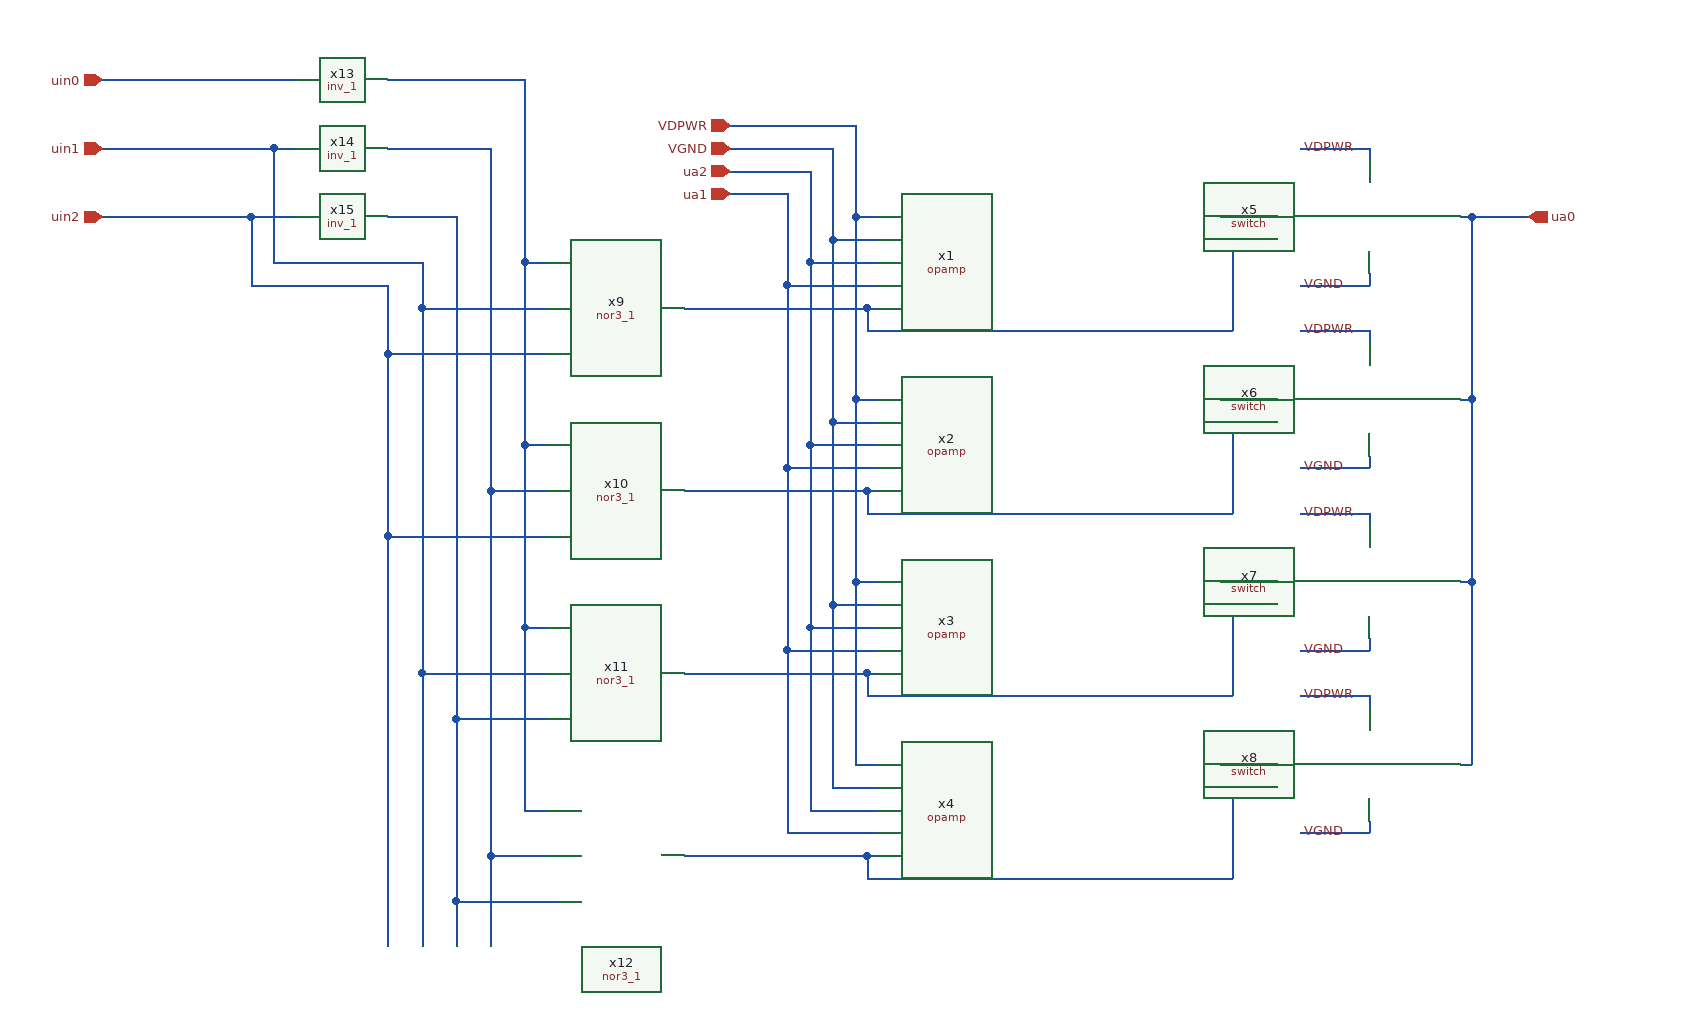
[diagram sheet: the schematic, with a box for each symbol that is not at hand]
v {xschem version=3.4.8RC file_version=1.3}
G {}
K {}
V {}
S {}
F {}
E {}
P 4 1 660 -260 {}
P 4 1 -670 -410 {}
N 60 180 80 180 {lab=VDPWR}
N 60 20 60 180 {lab=VDPWR}
N 60 -300 80 -300 {lab=VDPWR}
N 40 -280 80 -280 {lab=VGND}
N 40 40 40 200 {lab=VGND}
N 40 200 80 200 {lab=VGND}
N 40 40 80 40 {lab=VGND}
N 40 -120 40 40 {lab=VGND}
N 40 -120 80 -120 {lab=VGND}
N 60 -140 80 -140 {lab=VDPWR}
N 60 20 80 20 {lab=VDPWR}
N 60 -140 60 20 {lab=VDPWR}
N 20 60 80 60 {lab=ua2}
N 20 -100 20 60 {lab=ua2}
N 20 -260 80 -260 {lab=ua2}
N 0 -240 80 -240 {lab=ua1}
N 0 80 0 240 {lab=ua1}
N 0 240 80 240 {lab=ua1}
N 20 220 80 220 {lab=ua2}
N 20 60 20 220 {lab=ua2}
N 20 -100 80 -100 {lab=ua2}
N 70 -220 80 -220 {lab=#net1}
N 0 -80 80 -80 {lab=ua1}
N 0 -240 0 -80 {lab=ua1}
N 0 80 80 80 {lab=ua1}
N 0 -80 0 80 {lab=ua1}
N 70 -60 80 -60 {lab=#net2}
N 70 100 80 100 {lab=#net3}
N 70 260 80 260 {lab=#net4}
N 380 -300 430 -300 {lab=#net5}
N 390 -280 430 -280 {lab=#net1}
N 390 -280 390 -200 {lab=#net1}
N 70 -200 390 -200 {lab=#net1}
N 70 -220 70 -200 {lab=#net1}
N -90 -220 70 -220 {lab=#net1}
N 450 -360 510 -360 {lab=VDPWR}
N 510 -360 510 -350 {lab=VDPWR}
N 450 -240 510 -240 {lab=VGND}
N 510 -250 510 -240 {lab=VGND}
N 590 -300 600 -300 {lab=ua0}
N 600 -300 600 -140 {lab=ua0}
N 380 -140 430 -140 {lab=#net6}
N 390 -120 430 -120 {lab=#net2}
N 390 -120 390 -40 {lab=#net2}
N 70 -40 390 -40 {lab=#net2}
N 70 -60 70 -40 {lab=#net2}
N 450 -200 510 -200 {lab=VDPWR}
N 510 -200 510 -190 {lab=VDPWR}
N 450 -80 510 -80 {lab=VGND}
N 510 -90 510 -80 {lab=VGND}
N 590 -140 600 -140 {lab=ua0}
N 600 -140 600 20 {lab=ua0}
N -90 -60 70 -60 {lab=#net2}
N 380 20 430 20 {lab=#net7}
N 390 40 430 40 {lab=#net3}
N 390 40 390 120 {lab=#net3}
N 70 120 390 120 {lab=#net3}
N 70 100 70 120 {lab=#net3}
N 450 -40 510 -40 {lab=VDPWR}
N 510 -40 510 -30 {lab=VDPWR}
N 450 80 510 80 {lab=VGND}
N 510 70 510 80 {lab=VGND}
N 590 20 600 20 {lab=ua0}
N 600 20 600 180 {lab=ua0}
N -90 100 70 100 {lab=#net3}
N 390 200 430 200 {lab=#net4}
N 390 200 390 280 {lab=#net4}
N 450 120 510 120 {lab=VDPWR}
N 510 120 510 130 {lab=VDPWR}
N 450 240 510 240 {lab=VGND}
N 510 230 510 240 {lab=VGND}
N 590 180 600 180 {lab=ua0}
N 380 180 430 180 {lab=#net8}
N 70 280 390 280 {lab=#net4}
N 70 260 70 280 {lab=#net4}
N -90 260 70 260 {lab=#net4}
N 600 -300 650 -300 {lab=ua0}
N 60 -300 60 -140 {lab=VDPWR}
N 60 -380 60 -300 {lab=VDPWR}
N -50 -380 60 -380 {lab=VDPWR}
N 40 -280 40 -120 {lab=VGND}
N 40 -360 40 -280 {lab=VGND}
N -50 -360 40 -360 {lab=VGND}
N 20 -260 20 -100 {lab=ua2}
N 20 -340 20 -260 {lab=ua2}
N -50 -340 20 -340 {lab=ua2}
N -0 -320 -0 -240 {lab=ua1}
N -50 -320 -0 -320 {lab=ua1}
N -350 -420 -230 -420 {lab=#net9}
N -230 60 -230 220 {lab=#net9}
N -230 220 -210 220 {lab=#net9}
N -230 60 -210 60 {lab=#net9}
N -230 -100 -230 60 {lab=#net9}
N -230 -100 -210 -100 {lab=#net9}
N -230 -260 -230 -100 {lab=#net9}
N -230 -260 -210 -260 {lab=#net9}
N -230 -420 -230 -260 {lab=#net9}
N -350 -360 -260 -360 {lab=#net10}
N -260 260 -260 340 {lab=#net10}
N -350 -300 -290 -300 {lab=#net11}
N -290 300 -290 340 {lab=#net11}
N -450 -360 -430 -360 {lab=uin1}
N -600 -420 -430 -420 {lab=uin0}
N -470 -300 -430 -300 {lab=uin2}
N -450 -360 -450 -260 {lab=uin1}
N -600 -360 -450 -360 {lab=uin1}
N -450 -260 -320 -260 {lab=uin1}
N -320 100 -320 340 {lab=uin1}
N -470 -300 -470 -240 {lab=uin2}
N -600 -300 -470 -300 {lab=uin2}
N -470 -240 -350 -240 {lab=uin2}
N -350 -20 -350 340 {lab=uin2}
N -320 -220 -210 -220 {lab=uin1}
N -320 -260 -320 -220 {lab=uin1}
N -350 -180 -210 -180 {lab=uin2}
N -350 -240 -350 -180 {lab=uin2}
N -260 -60 -210 -60 {lab=#net10}
N -260 -360 -260 -60 {lab=#net10}
N -350 -20 -210 -20 {lab=uin2}
N -350 -180 -350 -20 {lab=uin2}
N -320 100 -210 100 {lab=uin1}
N -320 -220 -320 100 {lab=uin1}
N -290 140 -210 140 {lab=#net11}
N -290 -300 -290 140 {lab=#net11}
N -260 260 -210 260 {lab=#net10}
N -260 -60 -260 260 {lab=#net10}
N -290 300 -200 300 {lab=#net11}
N -290 140 -290 300 {lab=#net11}
C {/foss/designs/ttsky26c-analog-park/xschem/opamp.sym} 230 -260 0 0 {name=x1}
C {/foss/designs/ttsky26c-analog-park/xschem/opamp.sym} 230 -100 0 0 {name=x2}
C {/foss/designs/ttsky26c-analog-park/xschem/opamp.sym} 230 60 0 0 {name=x3}
C {/foss/designs/ttsky26c-analog-park/xschem/opamp.sym} 230 220 0 0 {name=x4}
C {/foss/designs/ttsky26c-analog-park/xschem/switch.sym} 510 -300 0 0 {name=x5}
C {lab_wire.sym} 450 -360 0 1 {name=p1 sig_type=std_logic lab=VDPWR}
C {lab_wire.sym} 450 -240 0 1 {name=p2 sig_type=std_logic lab=VGND}
C {/foss/designs/ttsky26c-analog-park/xschem/switch.sym} 510 -140 0 0 {name=x6}
C {lab_wire.sym} 450 -200 0 1 {name=p3 sig_type=std_logic lab=VDPWR}
C {lab_wire.sym} 450 -80 0 1 {name=p4 sig_type=std_logic lab=VGND}
C {/foss/designs/ttsky26c-analog-park/xschem/switch.sym} 510 20 0 0 {name=x7}
C {lab_wire.sym} 450 -40 0 1 {name=p5 sig_type=std_logic lab=VDPWR}
C {lab_wire.sym} 450 80 0 1 {name=p6 sig_type=std_logic lab=VGND}
C {/foss/designs/ttsky26c-analog-park/xschem/switch.sym} 510 180 0 0 {name=x8}
C {lab_wire.sym} 450 120 0 1 {name=p7 sig_type=std_logic lab=VDPWR}
C {lab_wire.sym} 450 240 0 1 {name=p8 sig_type=std_logic lab=VGND}
C {opin.sym} 650 -300 0 0 {name=p9 lab=ua0}
C {ipin.sym} -50 -380 0 0 {name=p10 lab=VDPWR
}
C {ipin.sym} -50 -360 0 0 {name=p11 lab=VGND
}
C {ipin.sym} -50 -320 0 0 {name=p12 lab=ua1
}
C {ipin.sym} -50 -340 0 0 {name=p13 lab=ua2
}
C {sky130_stdcells/nor3_1.sym} -150 -220 0 0 {name=x9 VGND=VGND VNB=VGND VPB=VDPWR VPWR=VDPWR prefix=sky130_fd_sc_hd__ }
C {sky130_stdcells/nor3_1.sym} -150 -60 0 0 {name=x10 VGND=VGND VNB=VGND VPB=VDPWR VPWR=VDPWR prefix=sky130_fd_sc_hd__ }
C {sky130_stdcells/nor3_1.sym} -150 100 0 0 {name=x11 VGND=VGND VNB=VGND VPB=VDPWR VPWR=VDPWR prefix=sky130_fd_sc_hd__ }
C {sky130_stdcells/nor3_1.sym} -150 260 0 0 {name=x12 VGND=VGND VNB=VGND VPB=VDPWR VPWR=VDPWR prefix=sky130_fd_sc_hd__ }
C {sky130_stdcells/inv_1.sym} -390 -420 0 0 {name=x13 VGND=VGND VNB=VGND VPB=VDPWR VPWR=VDPWR prefix=sky130_fd_sc_hd__ }
C {sky130_stdcells/inv_1.sym} -390 -360 0 0 {name=x14 VGND=VGND VNB=VGND VPB=VDPWR VPWR=VDPWR prefix=sky130_fd_sc_hd__ }
C {sky130_stdcells/inv_1.sym} -390 -300 0 0 {name=x15 VGND=VGND VNB=VGND VPB=VDPWR VPWR=VDPWR prefix=sky130_fd_sc_hd__ }
C {ipin.sym} -600 -420 0 0 {name=p14 lab=uin0
}
C {ipin.sym} -600 -360 0 0 {name=p15 lab=uin1
}
C {ipin.sym} -600 -300 0 0 {name=p16 lab=uin2
}
